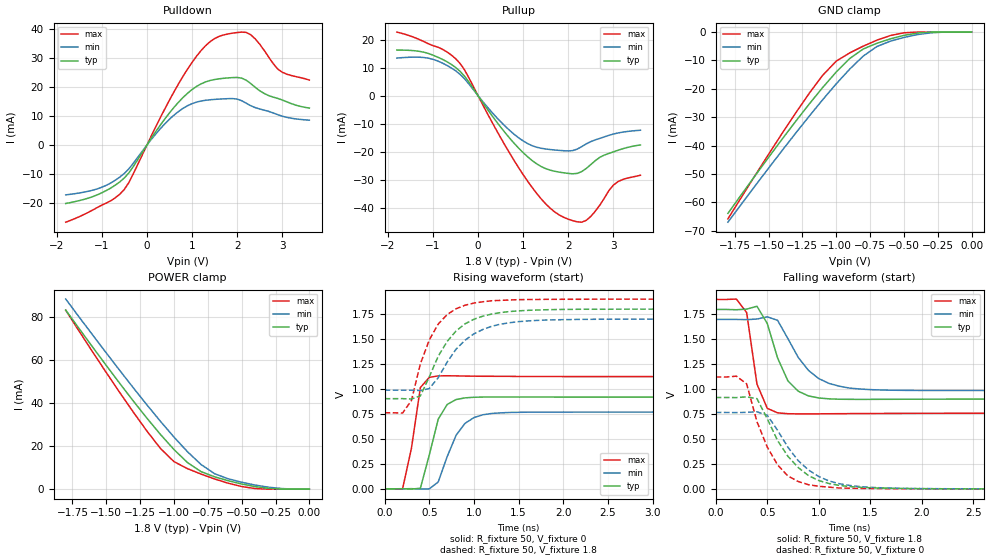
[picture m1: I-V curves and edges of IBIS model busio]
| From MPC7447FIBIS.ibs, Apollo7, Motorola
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| *   busio Model   *
[Model]   busio
Model_type   I/O
Polarity   Non-Inverting
Vinl = 0.63V
Vinh = 1.17V
Vmeas = 0.9V
Cref = 0
Rref = 50
Vref = 0.9V
|   typ   min   max
C_comp   4.247807e-12   3.413081e-12   4.406429e-12
|   typ   min   max
[Voltage range]   1.8V   1.7V   1.9V
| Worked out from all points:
|   slope of the pulldown table from 0 to 0.27 V, typ, clamps not added: 42.9 ohm
|   slope of the pullup table from 0 to 0.27 V, typ, clamps not added: 43.4 ohm
|   GND clamp passes 1 mA (typ) near -0.48 V on its own axis
|   POWER clamp passes 1 mA (typ) near -0.38 V on its own axis
|   falling waveform, R_fixture 50, V_fixture 1.8: 20-80 % time 192ps typ, 299ps min, 113ps max; typ from 1.8 V to 0.903 V
|   rising waveform, R_fixture 50, V_fixture 0: 20-80 % time 172ps typ, 232ps min, 125ps max; typ from 0 V to 0.918 V
|   falling waveform, R_fixture 50, V_fixture 0: 20-80 % time 355ps typ, 375ps min, 276ps max; typ from 0.918 V to 0 V
|   rising waveform, R_fixture 50, V_fixture 1.8: 20-80 % time 376ps typ, 402ps min, 295ps max; typ from 0.903 V to 1.8 V
[Pulldown]
|   Voltage   I(typ)   I(min)   I(max)
-1.8V     -20.22mA   -17.24mA   -26.68mA
-1V       -16.51mA   -14.59mA   -20.77mA
-500mV    -11.37mA   -9.803mA   -15.31mA
200mV     4.737mA    3.907mA    6.452mA
600mV     13.04mA    10.35mA    18.41mA
1.1V      20.29mA    14.85mA    30.74mA
1.5V      22.67mA    15.79mA    36.82mA
2V        23.38mA    15.9mA     38.91mA
2.2V      22.43mA    14.48mA    38.96mA
2.4V      19.97mA    12.95mA    36.73mA
2.9V      16.12mA    10.5mA     26.26mA
3.6V      12.8mA     8.605mA    22.47mA
[GND_clamp]
-1.8V     -63.88mA   -66.99mA   -65.83mA
-1.5V     -44.16mA   -47.97mA   -43.09mA
-1.3V     -31.49mA   -35.65mA   -28.55mA
-1.1V     -19.54mA   -23.83mA   -15.22mA
-1V       -14.07mA   -18.25mA   -10.25mA
-900mV    -9.309mA   -13.03mA   -7.322mA
-800mV    -5.947mA   -8.453mA   -4.95mA
-700mV    -3.949mA   -5.1mA     -2.867mA
-600mV    -2.397mA   -3.198mA   -1.214mA
-500mV    -1.157mA   -1.893mA   -247uA
-300mV    0A         -258.4uA   0A
0V        0A         0A         0A
[Pullup]
-1.8V     16.23mA    13.39mA    22.64mA
-1V       14.44mA    12.95mA    17.81mA
-700mV    12.18mA    10.87mA    15.69mA
-400mV    8.705mA    7.635mA    11.51mA
400mV     -9.061mA   -7.564mA   -12.06mA
900mV     -18.67mA   -15mA      -25.65mA
1.4V      -25.23mA   -18.73mA   -36.75mA
1.8V      -27.22mA   -19.48mA   -42.47mA
2.2V      -27.67mA   -19.02mA   -44.93mA
2.4V      -25.9mA    -17.15mA   -44.37mA
3V        -20.01mA   -13.66mA   -31.86mA
3.6V      -17.55mA   -12.3mA    -28.33mA
[POWER_clamp]
-1.8V     83.38mA    88.5mA     83.3mA
-1.5V     57.56mA    63.4mA     54.25mA
-1.3V     40.99mA    47.15mA    35.82mA
-1.1V     25.47mA    31.57mA    18.95mA
-1V       18.43mA    24.23mA    12.8mA
-900mV    12.36mA    17.4mA     9.538mA
-800mV    8.159mA    11.47mA    7.011mA
-700mV    5.755mA    7.198mA    4.745mA
-600mV    3.933mA    4.834mA    2.779mA
-400mV    1.18mA     1.903mA    284.4uA
-200mV    0A         271.1uA    0A
0V        0A         0A         0A
|   typ   min   max
[Ramp]
dV/dt_r   0.55081/1.51008e-10   0.46086/2.21412e-10   0.67414/8.09746e-11
dV/dt_f   0.53841/1.91446e-10   0.42720/2.92475e-10   0.68320/9.99337e-11
[Falling Waveform]
R_fixture = 50
V_fixture = 1.8
V_fixture_min = 1.7
V_fixture_max = 1.9
| time   V(typ)   V(min)   V(max)
0s        1.8V       1.7V       1.9V
200ps     1.797V     1.7V       1.904V
300ps     1.803V     1.698V     1.769V
400ps     1.832V     1.704V     1.052V
500ps     1.659V     1.726V     809.8mV
600ps     1.314V     1.691V     764.3mV
700ps     1.085V     1.508V     755.7mV
1ns       913.5mV    1.107V     754.7mV
1.6ns     900mV      993.6mV    758.4mV
19.7ns    902.6mV    988mV      761.3mV
[Rising Waveform]
R_fixture = 50
V_fixture = 0
V_fixture_min = 0
V_fixture_max = 0
| time   V(typ)   V(min)   V(max)
0s        216uV      232.5uV    163.6uV
200ps     1.283mV    -136.8uV   -3.354mV
300ps     -2.178mV   1.793mV    405.9mV
400ps     5.731mV    -2.24mV    1.014V
600ps     697.3mV    68.8mV     1.131V
700ps     844.8mV    322.6mV    1.132V
800ps     894.2mV    536.7mV    1.131V
900ps     910.7mV    655.7mV    1.129V
1.4ns     919.3mV    764.6mV    1.126V
19.7ns    918.2mV    768.3mV    1.124V
[Falling Waveform]
R_fixture = 50
V_fixture = 0
V_fixture_min = 0
V_fixture_max = 0
| time   V(typ)   V(min)   V(max)
0s        918.2mV    768.3mV    1.124V
200ps     917.3mV    766.8mV    1.132V
300ps     924.8mV    769.5mV    1.054V
400ps     906.5mV    775mV      675.8mV
500ps     705.1mV    740.1mV    421.7mV
700ps     329.4mV    420.4mV    132mV
900ps     136mV      192.1mV    44.54mV
1.2ns     37.67mV    54.6mV     11.6mV
2.5ns     3.149mV    3.359mV    2.195mV
19.7ns    228.4uV    246.1uV    169.7uV
[Rising Waveform]
R_fixture = 50
V_fixture = 1.8
V_fixture_min = 1.7
V_fixture_max = 1.9
| time   V(typ)   V(min)   V(max)
0s        902.6mV    988mV      761.3mV
200ps     902.9mV    987.6mV    758.4mV
300ps     899.6mV    988mV      884mV
400ps     930.4mV    984.3mV    1.251V
500ps     1.121V     1.004V     1.491V
700ps     1.476V     1.269V     1.745V
900ps     1.652V     1.488V     1.838V
1.2ns     1.75V      1.628V     1.883V
2.4ns     1.798V     1.698V     1.899V
19.7ns    1.8V       1.7V       1.9V
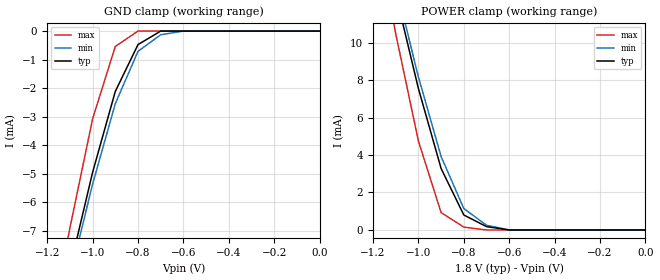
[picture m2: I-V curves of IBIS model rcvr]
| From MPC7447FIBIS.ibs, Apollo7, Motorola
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| *   rcvr  Model   *
[Model]   rcvr
Model_type   Input
Polarity   Non-Inverting
Vinl =   0.63V
Vinh =   1.17V
|   typ   min   max
C_comp   1.472126e-12   1.096168e-12   1.600808e-12
|   typ   min   max
[Voltage range]   1.8V   1.7V   1.9V
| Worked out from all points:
|   GND clamp passes 1 mA (typ) near -0.83 V on its own axis
|   POWER clamp passes 1 mA (typ) near -0.81 V on its own axis
|   Voltage(V)   I(typ)   I(min)   I(max)
[GND_clamp]
-1.8V     -35.01mA   -34.31mA   -38.57mA
-1.2V     -11.91mA   -12.08mA   -11.14mA
-1.1V     -8.313mA   -8.62mA    -6.904mA
-1V       -4.952mA   -5.364mA   -3.078mA
-900mV    -2.115mA   -2.545mA   -537.7uA
-800mV    -473.7uA   -709.1uA   0A
-700mV    0A         -127.9uA   0A
-600mV    0A         0A         0A
0V        0A         0A         0A
[POWER_clamp]
-1.8V     52.71mA    51.76mA    57.87mA
-1.2V     18mA       18.29mA    16.83mA
-1.1V     12.6mA     13.07mA    10.48mA
-1V       7.548mA    8.166mA    4.745mA
-900mV    3.28mA     3.918mA    927.7uA
-800mV    799.3uA    1.144mA    152.9uA
-700mV    179.2uA    251.8uA    0A
-600mV    0A         0A         0A
0V        0A         0A         0A
